VERSION 6.0 ;
BUSBITCHARS "[]" ;

UNITS
  DATABASE MICRONS 10000 ;
END UNITS

MANUFACTURINGGRID 0.0001 ;

CLEARANCEMEASURE EUCLIDEAN ;
USEMINSPACING OBS OFF ;

LAYER OVERLAP
  TYPE OVERLAP ;
END OVERLAP

PROPERTYDEFINITIONS
  LAYER LEF_CDN_WIDTH STRING ;
  LAYER LEF_CDN_BACKSIDE STRING ;
  LAYER LEF_CDN_TYPE STRING ;
  LAYER LEF58_WIDTH STRING ; 
END PROPERTYDEFINITIONS

LAYER DUMMY
  TYPE MASTERSLICE ;
END DUMMY


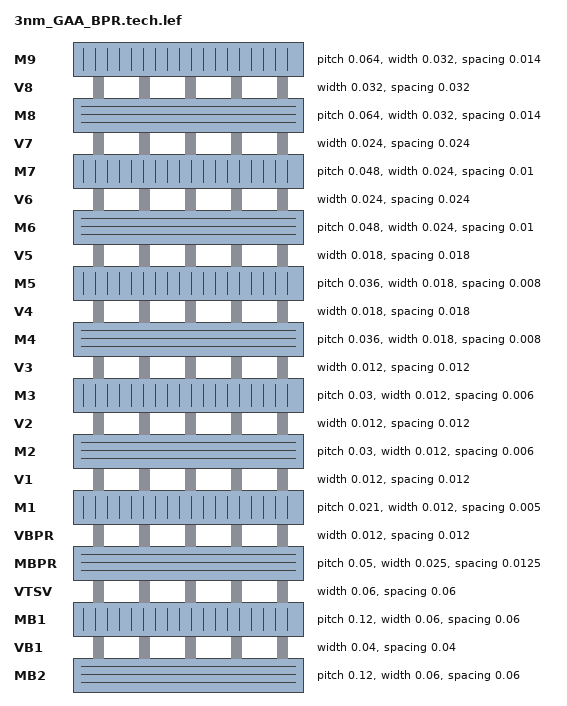
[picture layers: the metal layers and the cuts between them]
LAYER MB2
  TYPE ROUTING ;
  DIRECTION HORIZONTAL ;
  PITCH 0.12 ;
  WIDTH 0.06 ;
  SPACING 0.060 ;
  OFFSET 0 0 ;
  PROPERTY LEF_CDN_WIDTH "WIDTH 0.06 WRONGDIRECTION ;" ;
  PROPERTY LEF_CDN_BACKSIDE "BACKSIDE ; " ;
END MB2

LAYER VB1
  TYPE CUT ;
  WIDTH 0.04 ;
  SPACING 0.04 ;
  PROPERTY LEF_CDN_BACKSIDE "BACKSIDE ; " ;
END VB1

LAYER MB1
  TYPE ROUTING ;
  DIRECTION VERTICAL ;
  PITCH 0.12 ;
  WIDTH 0.06 ;
  SPACING 0.060 ;
  OFFSET 0 0 ;
  PROPERTY LEF_CDN_WIDTH "WIDTH 0.06 WRONGDIRECTION ;" ;
  PROPERTY LEF_CDN_BACKSIDE "BACKSIDE ; " ;
END MB1

LAYER VTSV
  TYPE CUT ;
  WIDTH 0.060 ;
  SPACING 0.060 ;
  PROPERTY LEF_CDN_TYPE "TYPE TSV LAYER MB1 MBPR ; " ;
END VTSV

LAYER MBPR
  TYPE ROUTING ;
  DIRECTION HORIZONTAL ;
  PITCH 0.050 ;
  WIDTH 0.025 ;
  SPACING 0.0125 ;
  OFFSET 0 0 ;
  PROPERTY LEF_CDN_WIDTH "WIDTH 0.025 WRONGDIRECTION ;" ;
END MBPR

LAYER VBPR
  TYPE CUT ;
  WIDTH 0.012 ;
  SPACING 0.012 ;
END VBPR


LAYER M1
  TYPE ROUTING ;
  DIRECTION VERTICAL ;
  PITCH 0.021 ;
  WIDTH 0.012 ;
  SPACING 0.005 ;
  OFFSET 0 0 ;
  PROPERTY LEF_CDN_WIDTH "WIDTH 0.012 WRONGDIRECTION ;" ;
END M1


LAYER V1
  TYPE CUT ;
  WIDTH 0.012 ;
  SPACING 0.012 ;
END V1

LAYER M2
  TYPE ROUTING ;
  DIRECTION HORIZONTAL ;
  PITCH 0.030 ;
  WIDTH 0.012 ;
  SPACING 0.006 ;
  OFFSET 0 0 ;
  PROPERTY LEF_CDN_WIDTH "WIDTH 0.012 WRONGDIRECTION ;" ;
END M2

LAYER V2
  TYPE CUT ;
  WIDTH 0.012 ;
  SPACING 0.012 ;
END V2

LAYER M3
  TYPE ROUTING ;
  DIRECTION VERTICAL ;
  PITCH 0.030 ;
  WIDTH 0.012 ;
  SPACING 0.006 ;
  OFFSET 0 0 ;
  PROPERTY LEF_CDN_WIDTH "WIDTH 0.012 WRONGDIRECTION ;" ;
END M3

LAYER V3
  TYPE CUT ;
  WIDTH 0.012 ;
  SPACING 0.012 ;
END V3

LAYER M4
  TYPE ROUTING ;
  DIRECTION HORIZONTAL ;
  PITCH 0.036 ;
  WIDTH 0.018 ;
  SPACING 0.008 ;
  OFFSET 0 0 ;
  PROPERTY LEF_CDN_WIDTH "WIDTH 0.018 WRONGDIRECTION ;" ;
END M4

LAYER V4
  TYPE CUT ;
  WIDTH 0.018 ;
  SPACING 0.018 ;
END V4

LAYER M5
  TYPE ROUTING ;
  DIRECTION VERTICAL ;
  PITCH 0.036 ;
  WIDTH 0.018 ;
  SPACING 0.008 ;
  OFFSET 0 0 ;
  PROPERTY LEF_CDN_WIDTH "WIDTH 0.018 WRONGDIRECTION ;" ;
END M5

LAYER V5
  TYPE CUT ;
  WIDTH 0.018 ;
  SPACING 0.018 ;
END V5

LAYER M6
  TYPE ROUTING ;
  DIRECTION HORIZONTAL ;
  PITCH 0.048 ;
  WIDTH 0.024 ;
  SPACING 0.010 ;
  OFFSET 0 0 ;
  PROPERTY LEF_CDN_WIDTH "WIDTH 0.024 WRONGDIRECTION ;" ;
END M6

LAYER V6
  TYPE CUT ;
  WIDTH 0.024 ;
  SPACING 0.024 ;
END V6

LAYER M7
  TYPE ROUTING ;
  DIRECTION VERTICAL ;
  PITCH 0.048 ;
  WIDTH 0.024 ;
  SPACING 0.010 ;
  OFFSET 0 0 ;
  PROPERTY LEF_CDN_WIDTH "WIDTH 0.024 WRONGDIRECTION ;" ;
END M7

LAYER V7
  TYPE CUT ;
  WIDTH 0.024 ;
  SPACING 0.024 ;
END V7

LAYER M8
  TYPE ROUTING ;
  DIRECTION HORIZONTAL ;
  PITCH 0.064 ;
  WIDTH 0.032 ;
  SPACING 0.014 ;
  OFFSET 0 0 ;
  PROPERTY LEF_CDN_WIDTH "WIDTH 0.032 WRONGDIRECTION ;" ;
END M8

LAYER V8
  TYPE CUT ;
  WIDTH 0.032 ;
  SPACING 0.032 ;
END V8

LAYER M9
  TYPE ROUTING ;
  DIRECTION VERTICAL ;
  PITCH 0.064 ;
  WIDTH 0.032 ;
  SPACING 0.014 ;
  OFFSET 0 0 ;
  PROPERTY LEF_CDN_WIDTH "WIDTH 0.032 WRONGDIRECTION ;" ;
END M9


VIA M9_M8
  LAYER M8 ;
    RECT -0.025 -0.016 0.025 0.016 ;
  LAYER V8 ;
    RECT -0.016 -0.016 0.016 0.016 ;
  LAYER M9 ;
    RECT -0.016 -0.025 0.016 0.025 ;
END M9_M8

VIA M8_M7
  LAYER M7 ;
    RECT -0.012 -0.019 0.012 0.019 ;
  LAYER V7 ;
    RECT -0.012 -0.012 0.012 0.012 ;
  LAYER M8 ;
    RECT -0.021 -0.012 0.021 0.012 ;
END M8_M7

VIA M7_M6
  LAYER M6 ;
    RECT -0.019 -0.012 0.019 0.012 ;
  LAYER V6 ;
    RECT -0.012 -0.012 0.012 0.012 ;
  LAYER M7 ;
    RECT -0.012 -0.019 0.012 0.019 ;
END M7_M6

VIA M6_M5
  LAYER M5 ;
    RECT -0.009 -0.014 0.009 0.014 ;
  LAYER V5 ;
    RECT -0.009 -0.009 0.009 0.009 ;
  LAYER M6 ;
    RECT -0.016 -0.009 0.016 0.009 ;
END M6_M5

VIA M5_M4
  LAYER M4 ;
    RECT -0.014 -0.009 0.014 0.009 ;
  LAYER V4 ;
    RECT -0.009 -0.009 0.009 0.009 ;
  LAYER M5 ;
    RECT -0.009 -0.014 0.009 0.014 ;
END M5_M4

VIA M4_M3
  LAYER M3 ;
    RECT -0.006 -0.009 0.006 0.009 ;
  LAYER V3 ;
    RECT -0.006 -0.006 0.006 0.006 ;
  LAYER M4 ;
    RECT -0.011 -0.006 0.011 0.006 ;
END M4_M3

VIA M3_M2
  LAYER M2 ;
    RECT -0.009 -0.006 0.009 0.006 ;
  LAYER V2 ;
    RECT -0.006 -0.006 0.006 0.006 ;
  LAYER M3 ;
    RECT -0.006 -0.009 0.006 0.009 ;
END M3_M2

VIA M2_M1
  LAYER M1 ;
    RECT -0.006 -0.009 0.006 0.009 ;
  LAYER V1 ;
    RECT -0.006 -0.006 0.006 0.006 ;
  LAYER M2 ;
    RECT -0.009 -0.006 0.009 0.006 ;
END M2_M1

VIA M1_MBPR
  LAYER MBPR ;
    RECT -0.009 -0.010 0.009 0.010 ;
  LAYER VBPR ;
    RECT -0.006 -0.010 0.006 0.010 ;
  LAYER M1 ;
    RECT -0.006 -0.013 0.006 0.013 ;
END M1_MBPR


VIA MBPR_MB1
  LAYER MB1 ;
    RECT -0.030 -0.033 0.030 0.033 ;
  LAYER VTSV ;
    RECT -0.030 -0.030 0.030 0.030 ;
  LAYER MBPR ;
    RECT -0.033 -0.030 0.033 0.030 ;
END MBPR_MB1

VIA MB1_MB2
  LAYER MB2 ;
    RECT -0.045 -0.030 0.045 0.030 ;
  LAYER VB1 ;
    RECT -0.020 -0.020 0.020 0.020 ;
  LAYER MB1 ;
    RECT -0.030 -0.045 0.030 0.045 ;
END MB1_MB2






VIARULE V8GEN GENERATE DEFAULT
  LAYER M8 ;
	  ENCLOSURE 0.009 0.000 ;
  LAYER V8 ;
    RECT -0.016 -0.016 0.016 0.016 ;
    SPACING 0.032 BY 0.032 ;
  LAYER M9 ;
    ENCLOSURE 0.000 0.009 ;
END V8GEN

VIARULE V7GEN GENERATE DEFAULT
  LAYER M7 ;
	  ENCLOSURE 0.000 0.007 ;
  LAYER V7 ;
    RECT -0.012 -0.012 0.012 0.012 ;
    SPACING 0.024 BY 0.024 ;
  LAYER M8 ;
    ENCLOSURE 0.009 0.000 ;
END V7GEN

VIARULE V6GEN GENERATE DEFAULT
  LAYER M6 ;
	  ENCLOSURE 0.007 0.000 ;
  LAYER V6 ;
    RECT -0.012 -0.012 0.012 0.012 ;
    SPACING 0.024 BY 0.024 ;
  LAYER M7 ;
    ENCLOSURE 0.000 0.007 ;
END V6GEN

VIARULE V5GEN GENERATE DEFAULT
  LAYER M5 ;
	  ENCLOSURE 0.000 0.005 ;
  LAYER V5 ;
    RECT -0.009 -0.009 0.009 0.009 ;
    SPACING 0.018 BY 0.018 ;
  LAYER M6 ;
    ENCLOSURE 0.007 0.000 ;
END V5GEN

VIARULE V4GEN GENERATE DEFAULT
  LAYER M4 ;
	  ENCLOSURE 0.005 0.000 ;
  LAYER V4 ;
    RECT -0.009 -0.009 0.009 0.009 ;
    SPACING 0.018 BY 0.018 ;
  LAYER M5 ;
    ENCLOSURE 0.000 0.005 ;
END V4GEN

VIARULE V3GEN GENERATE DEFAULT
  LAYER M3 ;
	  ENCLOSURE 0.000 0.003 ;
  LAYER V3 ;
    RECT -0.006 -0.006 0.006 0.006 ;
    SPACING 0.012 BY 0.012 ;
  LAYER M4 ;
    ENCLOSURE 0.005 0.000 ;
END V3GEN

VIARULE V2GEN GENERATE DEFAULT
  LAYER M2 ;
	  ENCLOSURE 0.003 0.000 ;
  LAYER V2 ;
    RECT -0.006 -0.006 0.006 0.006 ;
    SPACING 0.012 BY 0.012 ;
  LAYER M3 ;
    ENCLOSURE 0.000 0.003 ;
END V2GEN

VIARULE V1GEN GENERATE DEFAULT
  LAYER M1 ;
	  ENCLOSURE 0.000 0.003 ;
  LAYER V1 ;
    RECT -0.006 -0.006 0.006 0.006 ;
    SPACING 0.012 BY 0.012 ;
  LAYER M2 ;
    ENCLOSURE 0.003 0.000 ;
END V1GEN

VIARULE VBPRGEN GENERATE DEFAULT
  LAYER MBPR ;
    ENCLOSURE 0.003 0.000 ;
  LAYER VBPR ;
    RECT -0.006 -0.010 0.006 0.010 ;
    SPACING 0.012 BY 0.020 ;
  LAYER M1 ;
    ENCLOSURE 0.000 0.003 ;
END VBPRGEN


VIARULE VTSVGEN GENERATE DEFAULT
  LAYER MB1 ;
    ENCLOSURE 0.000 0.003 ;
  LAYER VTSV ;
    RECT -0.030 -0.030 0.030 0.030 ;
    SPACING 0.060 BY 0.060 ;
  LAYER MBPR ;
    ENCLOSURE 0.003 0.000 ;
END VTSVGEN

VIARULE VB1GEN GENERATE DEFAULT
  LAYER MB2 ;
    ENCLOSURE 0.010 0.000 ;
  LAYER VB1 ;
    RECT -0.020 -0.020 0.020 0.020 ;
    SPACING 0.040 BY 0.040 ;
  LAYER MB1 ;
    ENCLOSURE 0.000 0.010 ;
END VB1GEN



SITE coreSite
  CLASS CORE ;
  SYMMETRY Y ;
  SIZE 0.042 BY 0.120 ;
END coreSite

END LIBRARY
